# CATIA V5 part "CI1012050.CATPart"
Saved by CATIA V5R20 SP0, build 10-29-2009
Part number: CI1012050
Bounding box of the stored display mesh (mm): x -12 to 12, y -10.269 to 68, z -13.002 to 14.106
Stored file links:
  C:\Users\Raffaele\Desktop\3D X SITO CF\BOLEX\19-INCLINED ASSEMBLY REF_CI\CI1012050.CATPart

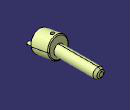
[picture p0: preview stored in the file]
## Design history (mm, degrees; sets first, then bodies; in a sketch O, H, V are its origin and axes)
Set1
  DatumSurface1 to DatumSurface16 "MANIFOLD_SOLID_BREP #377"
  DatumSurface17 to DatumSurface39 "MANIFOLD_SOLID_BREP #1094"
Body1 (main body)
